VERSION 5.7 ;
  NOWIREEXTENSIONATPIN ON ;
  DIVIDERCHAR "/" ;
  BUSBITCHARS "[]" ;
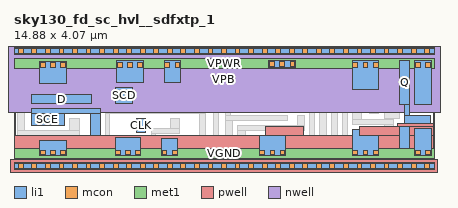
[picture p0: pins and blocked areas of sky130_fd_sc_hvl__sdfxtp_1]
MACRO sky130_fd_sc_hvl__sdfxtp_1
  CLASS BLOCK ;
  FOREIGN sky130_fd_sc_hvl__sdfxtp_1 ;
  ORIGIN 0.000 0.000 ;
  SIZE 14.880 BY 4.070 ;
  PIN CLK
    ANTENNAGATEAREA 0.585000 ;
    PORT
      LAYER li1 ;
        RECT 4.345 1.175 4.675 1.685 ;
    END
  END CLK
  PIN D
    ANTENNAGATEAREA 0.420000 ;
    PORT
      LAYER li1 ;
        RECT 0.605 2.205 2.755 2.520 ;
    END
  END D
  PIN SCD
    ANTENNAGATEAREA 0.420000 ;
    PORT
      LAYER li1 ;
        RECT 3.600 2.215 4.195 2.765 ;
    END
  END SCD
  PIN SCE
    ANTENNAGATEAREA 0.840000 ;
    PORT
      LAYER li1 ;
        RECT 0.605 1.855 3.050 2.025 ;
        RECT 0.605 1.445 1.795 1.855 ;
        RECT 2.720 1.095 3.050 1.855 ;
    END
  END SCE
  PIN VGND
    USE GROUND ;
    PORT
      LAYER li1 ;
        RECT 0.905 0.365 1.855 0.915 ;
        RECT 3.580 0.365 4.485 0.995 ;
        RECT 5.215 0.365 5.805 0.975 ;
        RECT 8.680 0.365 9.630 1.075 ;
        RECT 11.980 0.365 12.930 1.305 ;
        RECT 14.200 0.365 14.790 1.325 ;
      LAYER mcon ;
        RECT 0.935 0.395 1.105 0.565 ;
        RECT 1.295 0.395 1.465 0.565 ;
        RECT 1.655 0.395 1.825 0.565 ;
        RECT 3.590 0.395 3.760 0.565 ;
        RECT 3.950 0.395 4.120 0.565 ;
        RECT 4.310 0.395 4.480 0.565 ;
        RECT 5.245 0.395 5.415 0.565 ;
        RECT 5.605 0.395 5.775 0.565 ;
        RECT 8.710 0.395 8.880 0.565 ;
        RECT 9.070 0.395 9.240 0.565 ;
        RECT 9.430 0.395 9.600 0.565 ;
        RECT 12.010 0.395 12.180 0.565 ;
        RECT 12.370 0.395 12.540 0.565 ;
        RECT 12.730 0.395 12.900 0.565 ;
        RECT 14.230 0.395 14.400 0.565 ;
        RECT 14.590 0.395 14.760 0.565 ;
      LAYER met1 ;
        RECT 0.000 0.255 14.880 0.625 ;
    END
  END VGND
  PIN VNB
    ANTENNADIFFAREA 2.529600 ;
    PORT
      LAYER pwell ;
        RECT 13.570 1.415 14.860 1.515 ;
        RECT 8.920 1.085 10.250 1.415 ;
        RECT 12.240 1.085 14.860 1.415 ;
        RECT 0.035 0.215 14.860 1.085 ;
        RECT -0.130 -0.215 15.010 0.215 ;
      LAYER li1 ;
        RECT 0.000 -0.085 14.880 0.085 ;
      LAYER mcon ;
        RECT 0.155 -0.085 0.325 0.085 ;
        RECT 0.635 -0.085 0.805 0.085 ;
        RECT 1.115 -0.085 1.285 0.085 ;
        RECT 1.595 -0.085 1.765 0.085 ;
        RECT 2.075 -0.085 2.245 0.085 ;
        RECT 2.555 -0.085 2.725 0.085 ;
        RECT 3.035 -0.085 3.205 0.085 ;
        RECT 3.515 -0.085 3.685 0.085 ;
        RECT 3.995 -0.085 4.165 0.085 ;
        RECT 4.475 -0.085 4.645 0.085 ;
        RECT 4.955 -0.085 5.125 0.085 ;
        RECT 5.435 -0.085 5.605 0.085 ;
        RECT 5.915 -0.085 6.085 0.085 ;
        RECT 6.395 -0.085 6.565 0.085 ;
        RECT 6.875 -0.085 7.045 0.085 ;
        RECT 7.355 -0.085 7.525 0.085 ;
        RECT 7.835 -0.085 8.005 0.085 ;
        RECT 8.315 -0.085 8.485 0.085 ;
        RECT 8.795 -0.085 8.965 0.085 ;
        RECT 9.275 -0.085 9.445 0.085 ;
        RECT 9.755 -0.085 9.925 0.085 ;
        RECT 10.235 -0.085 10.405 0.085 ;
        RECT 10.715 -0.085 10.885 0.085 ;
        RECT 11.195 -0.085 11.365 0.085 ;
        RECT 11.675 -0.085 11.845 0.085 ;
        RECT 12.155 -0.085 12.325 0.085 ;
        RECT 12.635 -0.085 12.805 0.085 ;
        RECT 13.115 -0.085 13.285 0.085 ;
        RECT 13.595 -0.085 13.765 0.085 ;
        RECT 14.075 -0.085 14.245 0.085 ;
        RECT 14.555 -0.085 14.725 0.085 ;
      LAYER met1 ;
        RECT 0.000 -0.115 14.880 0.115 ;
    END
  END VNB
  PIN VPB
    ANTENNADIFFAREA 2.529600 ;
    PORT
      LAYER nwell ;
        RECT -0.330 1.885 15.210 4.485 ;
      LAYER li1 ;
        RECT 0.000 3.985 14.880 4.155 ;
      LAYER mcon ;
        RECT 0.155 3.985 0.325 4.155 ;
        RECT 0.635 3.985 0.805 4.155 ;
        RECT 1.115 3.985 1.285 4.155 ;
        RECT 1.595 3.985 1.765 4.155 ;
        RECT 2.075 3.985 2.245 4.155 ;
        RECT 2.555 3.985 2.725 4.155 ;
        RECT 3.035 3.985 3.205 4.155 ;
        RECT 3.515 3.985 3.685 4.155 ;
        RECT 3.995 3.985 4.165 4.155 ;
        RECT 4.475 3.985 4.645 4.155 ;
        RECT 4.955 3.985 5.125 4.155 ;
        RECT 5.435 3.985 5.605 4.155 ;
        RECT 5.915 3.985 6.085 4.155 ;
        RECT 6.395 3.985 6.565 4.155 ;
        RECT 6.875 3.985 7.045 4.155 ;
        RECT 7.355 3.985 7.525 4.155 ;
        RECT 7.835 3.985 8.005 4.155 ;
        RECT 8.315 3.985 8.485 4.155 ;
        RECT 8.795 3.985 8.965 4.155 ;
        RECT 9.275 3.985 9.445 4.155 ;
        RECT 9.755 3.985 9.925 4.155 ;
        RECT 10.235 3.985 10.405 4.155 ;
        RECT 10.715 3.985 10.885 4.155 ;
        RECT 11.195 3.985 11.365 4.155 ;
        RECT 11.675 3.985 11.845 4.155 ;
        RECT 12.155 3.985 12.325 4.155 ;
        RECT 12.635 3.985 12.805 4.155 ;
        RECT 13.115 3.985 13.285 4.155 ;
        RECT 13.595 3.985 13.765 4.155 ;
        RECT 14.075 3.985 14.245 4.155 ;
        RECT 14.555 3.985 14.725 4.155 ;
      LAYER met1 ;
        RECT 0.000 3.955 14.880 4.185 ;
    END
  END VPB
  PIN VPWR
    USE POWER ;
    PORT
      LAYER li1 ;
        RECT 0.910 2.925 1.860 3.705 ;
        RECT 3.635 2.945 4.585 3.735 ;
        RECT 5.315 2.945 5.905 3.735 ;
        RECT 9.030 3.505 9.980 3.755 ;
        RECT 11.980 2.695 12.930 3.735 ;
        RECT 14.200 2.195 14.790 3.735 ;
      LAYER mcon ;
        RECT 0.940 3.505 1.110 3.675 ;
        RECT 1.300 3.505 1.470 3.675 ;
        RECT 1.660 3.505 1.830 3.675 ;
        RECT 3.665 3.505 3.835 3.675 ;
        RECT 4.025 3.505 4.195 3.675 ;
        RECT 4.385 3.505 4.555 3.675 ;
        RECT 5.345 3.505 5.515 3.675 ;
        RECT 5.705 3.505 5.875 3.675 ;
        RECT 9.060 3.535 9.230 3.705 ;
        RECT 9.420 3.535 9.590 3.705 ;
        RECT 9.780 3.535 9.950 3.705 ;
        RECT 12.010 3.505 12.180 3.675 ;
        RECT 12.370 3.505 12.540 3.675 ;
        RECT 12.730 3.505 12.900 3.675 ;
        RECT 14.230 3.505 14.400 3.675 ;
        RECT 14.590 3.505 14.760 3.675 ;
      LAYER met1 ;
        RECT 0.000 3.445 14.880 3.815 ;
    END
  END VPWR
  PIN Q
    ANTENNADIFFAREA 0.596250 ;
    PORT
      LAYER li1 ;
        RECT 13.660 2.195 14.020 3.735 ;
        RECT 13.850 1.780 14.020 2.195 ;
        RECT 13.850 1.505 14.755 1.780 ;
        RECT 13.660 0.615 14.020 1.505 ;
    END
  END Q
  OBS
      LAYER li1 ;
        RECT 0.125 1.265 0.380 3.425 ;
        RECT 2.400 3.095 2.730 3.425 ;
        RECT 2.400 2.925 3.400 3.095 ;
        RECT 3.230 2.035 3.400 2.925 ;
        RECT 4.765 2.765 5.095 3.735 ;
        RECT 6.095 3.505 6.425 3.735 ;
        RECT 6.095 3.335 7.325 3.505 ;
        RECT 6.095 2.945 6.425 3.335 ;
        RECT 4.765 2.595 5.605 2.765 ;
        RECT 5.275 2.215 5.605 2.595 ;
        RECT 6.610 2.695 6.975 3.155 ;
        RECT 6.610 2.035 6.780 2.695 ;
        RECT 7.155 2.515 7.325 3.335 ;
        RECT 10.320 3.325 11.450 3.495 ;
        RECT 6.960 2.225 7.325 2.515 ;
        RECT 7.505 2.675 7.755 3.175 ;
        RECT 8.040 3.155 10.490 3.325 ;
        RECT 3.230 1.865 6.780 2.035 ;
        RECT 1.975 1.265 2.305 1.675 ;
        RECT 0.125 1.095 2.305 1.265 ;
        RECT 0.125 0.515 0.455 1.095 ;
        RECT 3.230 0.915 3.400 1.865 ;
        RECT 5.540 1.325 5.870 1.685 ;
        RECT 4.855 1.155 5.870 1.325 ;
        RECT 4.855 0.975 5.025 1.155 ;
        RECT 6.565 0.995 6.780 1.865 ;
        RECT 2.395 0.745 3.400 0.915 ;
        RECT 2.395 0.495 2.725 0.745 ;
        RECT 4.665 0.515 5.025 0.975 ;
        RECT 5.995 0.435 6.325 0.975 ;
        RECT 6.565 0.615 6.895 0.995 ;
        RECT 7.075 0.435 7.245 2.225 ;
        RECT 7.505 1.775 7.675 2.675 ;
        RECT 8.040 2.495 8.210 3.155 ;
        RECT 9.810 2.675 10.140 2.975 ;
        RECT 7.880 1.955 8.210 2.495 ;
        RECT 8.620 2.125 8.950 2.555 ;
        RECT 9.810 2.125 9.980 2.675 ;
        RECT 10.320 2.495 10.490 3.155 ;
        RECT 10.670 2.675 11.075 3.145 ;
        RECT 10.160 2.305 10.490 2.495 ;
        RECT 8.620 1.955 10.645 2.125 ;
        RECT 7.505 1.605 9.685 1.775 ;
        RECT 7.505 0.995 7.755 1.605 ;
        RECT 10.045 1.425 10.295 1.775 ;
        RECT 7.425 0.615 7.755 0.995 ;
        RECT 7.935 1.255 10.295 1.425 ;
        RECT 7.935 0.435 8.210 1.255 ;
        RECT 10.475 1.075 10.645 1.955 ;
        RECT 9.810 0.905 10.645 1.075 ;
        RECT 9.810 0.495 10.140 0.905 ;
        RECT 10.825 0.665 11.075 2.675 ;
        RECT 11.255 1.085 11.450 3.325 ;
        RECT 11.630 2.345 12.930 2.515 ;
        RECT 11.630 0.665 11.800 2.345 ;
        RECT 11.980 1.655 12.310 2.155 ;
        RECT 12.600 1.845 12.930 2.345 ;
        RECT 13.110 2.015 13.440 3.735 ;
        RECT 13.110 1.685 13.670 2.015 ;
        RECT 13.110 1.655 13.440 1.685 ;
        RECT 11.980 1.485 13.440 1.655 ;
        RECT 10.825 0.495 11.800 0.665 ;
        RECT 13.110 0.515 13.440 1.485 ;
        RECT 5.995 0.265 8.210 0.435 ;
  END
END sky130_fd_sc_hvl__sdfxtp_1
END LIBRARY

